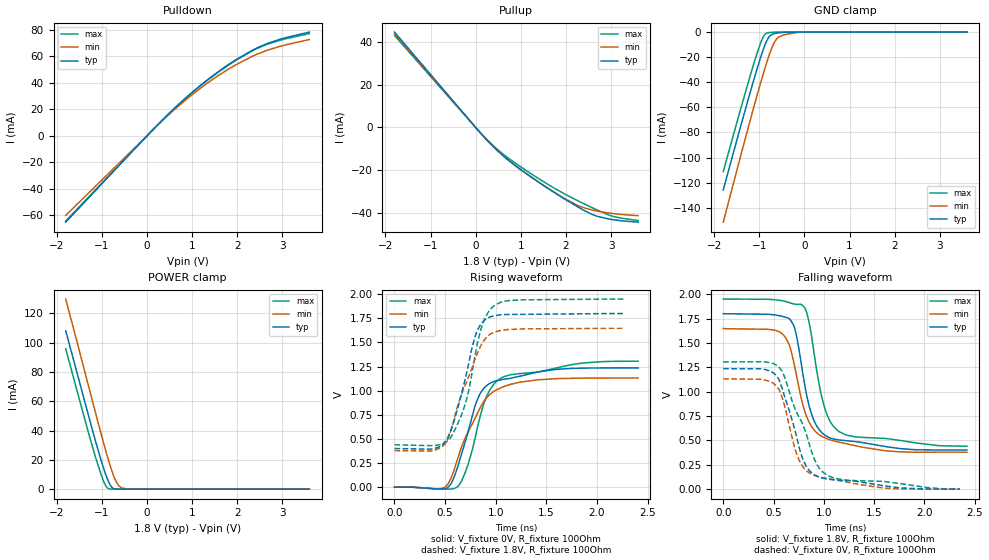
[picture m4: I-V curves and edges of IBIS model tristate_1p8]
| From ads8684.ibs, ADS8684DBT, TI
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|   tristate_1p8 Model
[Model]   tristate_1p8
Model_type   3-state
Polarity   Non-Inverting
Vmeas = 0.9
Vref = 0
Cref = 20pF
Rref = 100
|   typ   min   max
|   (nom PVT)   (fast PVT)   (slow PVT)
C_comp   1.371e-12   1.006e-12   1.720e-12
| Where nom  PVT is Nominal Process, 1.8V, 27C
|   Fast PVT is Strong Process,  1.95V, -40C
|   Slow PVT is Weak Process,   1.65V, 125C
[Voltage Range]   1.8   1.65   1.95
|Junction Temperature
[Temperature Range]   27   125   -40
[Pullup Reference]   1.8   1.65   1.95
[Pulldown Reference]   0   0   0
[Power Clamp Reference]   1.8   1.65   1.95
[GND Clamp Reference]   0   0   0
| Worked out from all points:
|   slope of the pulldown table from 0 to 0.27 V, typ, clamps not added: 28.3 ohm
|   slope of the pullup table from 0 to 0.27 V, typ, clamps not added: 42.5 ohm
|   GND clamp passes 1 mA (typ) near -0.64 V on its own axis
|   POWER clamp passes 1 mA (typ) near -0.76 V on its own axis
|   falling waveform, V_fixture 1.8V, R_fixture 100Ohm: 20-80 % time 175ps typ, 205ps min, 176ps max; typ from 1.8 V to 0.401 V
|   rising waveform, V_fixture 0V, R_fixture 100Ohm: 20-80 % time 222ps typ, 291ps min, 232ps max; typ from 0 V to 1.24 V
|   rising waveform, V_fixture 1.8V, R_fixture 100Ohm: 20-80 % time 199ps typ, 250ps min, 198ps max; typ from 0.401 V to 1.8 V
|   falling waveform, V_fixture 0V, R_fixture 100Ohm: 20-80 % time 220ps typ, 199ps min, 285ps max; typ from 1.24 V to 0 V
[Pulldown]
|   Voltage   I(typ)   I(min)   I(max)
-1.8V     -65.09mA   -59.97mA   -64.2mA
252mV     8.924mA    8.498mA    8.811mA
708mV     23.94mA    22.75mA    23.68mA
1.33V     41.95mA    39.55mA    41.59mA
1.979V    57.51mA    53.74mA    57.14mA
2.453V    66.54mA    61.79mA    66.14mA
2.919V    72.5mA     67.21mA    71.79mA
3.6V      78.26mA    72.63mA    77.11mA
[GND Clamp]
|   Voltage   I(typ)   I(min)   I(max)
-1.8V     -125.8mA   -151.5mA   -111.2mA
-1.188V   -46.12mA   -68.35mA   -32.95mA
-1.039V   -27.91mA   -48.94mA   -15.6mA
-956.8mV  -18.56mA   -38.63mA   -7.307mA
-877.7mV  -10.45mA   -29.02mA   -1.892mA
-786mV    -3.851mA   -18.72mA   -422.1uA
-682.9mV  -1.398mA   -9.3mA     -99.75uA
-612mV    -832uA     -5.278mA   -21.92uA
-567.5mV  -603uA     -3.872mA   -6.378uA
-432.1mV  -155.8uA   -1.97mA    -62.9nA
-150uV    0A         0A         0A
3.6V      0A         0A         0A
[Pullup]
|   Voltage   I(typ)   I(min)   I(max)
-1.8V     44.52mA    43.7mA     42.93mA
144mV     -3.484mA   -3.429mA   -3.353mA
523.2mV   -11.59mA   -11.51mA   -10.98mA
924.2mV   -18.47mA   -18.58mA   -17.31mA
1.764V    -30.63mA   -30.51mA   -28.59mA
2.279V    -37.25mA   -36.57mA   -34.36mA
2.691V    -41.43mA   -39.01mA   -38.5mA
3.065V    -43.1mA    -40.22mA   -41.59mA
3.6V      -44.19mA   -41.16mA   -43.4mA
[POWER Clamp]
|   Voltage   I(typ)   I(min)   I(max)
-1.8V     108.1mA    129.7mA    95.71mA
-1.201V   39.66mA    59.35mA    28.24mA
-1.105V   29.06mA    48.08mA    18.49mA
-969.3mV  15.12mA    32.48mA    6.171mA
-921.6mV  10.73mA    27.2mA     2.821mA
-875.7mV  6.912mA    22.27mA    808.1uA
-786.9mV  1.628mA    13.43mA    15.62uA
-691.2mV  86.61uA    5.777mA    145.8nA
-610.3mV  4.558uA    1.946mA    0A
-565.6mV  916.7nA    930.5uA    0A
-465.2mV  29.51nA    207.3uA    0A
3.6V      0A         0A         0A
[Ramp]
R_load = 100
|   typ   min   max
dV/dt_r   0.741646/2.21853e-10   0.679044/2.91169e-10   0.782971/2.29874e-10
dV/dt_f   0.839441/1.74617e-10   0.760625/2.04263e-10   0.906149/1.75559e-10
[Falling Waveform]
V_fixture = 1.8V
V_fixture_min = 1.65V
V_fixture_max = 1.95V
R_fixture = 100Ohm
|   Time   V(typ)   V(min)   V(max)
0s        1.8V       1.65V      1.95V
604.5ps   1.768V     1.575V     1.929V
704ps     1.671V     1.286V     1.899V
796.5ps   1.15V      845.9mV    1.877V
880ps     763.1mV    639.8mV    1.553V
957.5ps   604.9mV    556mV      1.051V
1.012ns   553mV      526.6mV    823.7mV
1.092ns   516.5mV    498.3mV    648.8mV
1.223ns   497.3mV    466.3mV    554.7mV
2.422ns   401.5mV    379.4mV    440.5mV
[Rising Waveform]
V_fixture = 0V
V_fixture_min = 0V
V_fixture_max = 0V
R_fixture = 100Ohm
|   Time   V(typ)   V(min)   V(max)
0s        1.026nV    295.3nV    1.107nV
488ps     -16.25mV   -5.595mV   -20.24mV
556.5ps   32.29mV    88.5mV     -18.33mV
629.5ps   227.5mV    312.2mV    11.1mV
727ps     574.9mV    572.8mV    237.3mV
816.5ps   901.8mV    757.9mV    607.9mV
943.5ps   1.078V     962.1mV    1.011V
1.144ns   1.129V     1.065V     1.165V
1.581ns   1.219V     1.124V     1.231V
2.407ns   1.236V     1.132V     1.306V
[Rising Waveform]
V_fixture = 1.8V
V_fixture_min = 1.65V
V_fixture_max = 1.95V
R_fixture = 100Ohm
|   Time   V(typ)   V(min)   V(max)
0s        400.9mV    379mV      439.8mV
402.5ps   403.7mV    385.8mV    432.9mV
502ps     472.1mV    450.7mV    463.4mV
546ps     560.1mV    550.7mV    502.3mV
701.5ps   1.134V     1.064V     870.4mV
808ps     1.597V     1.36V      1.431V
885.5ps   1.727V     1.523V     1.733V
991ps     1.778V     1.609V     1.886V
1.256ns   1.791V     1.64V      1.942V
2.271ns   1.8V       1.646V     1.95V
[Falling Waveform]
V_fixture = 0V
V_fixture_min = 0V
V_fixture_max = 0V
R_fixture = 100Ohm
|   Time   V(typ)   V(min)   V(max)
0s        1.236V     1.132V     1.305V
415.5ps   1.227V     1.119V     1.305V
556.5ps   1.117V     1.017V     1.247V
605ps     966.2mV    872mV      1.163V
756ps     420mV      294.2mV    734.2mV
839.5ps   211.9mV    178.8mV    519.9mV
936.5ps   131.2mV    131mV      244mV
1.114ns   94.44mV    95.3mV     109.9mV
1.603ns   33.97mV    10.87mV    78.51mV
2.351ns   5.752nV    481.5nV    2.812nV
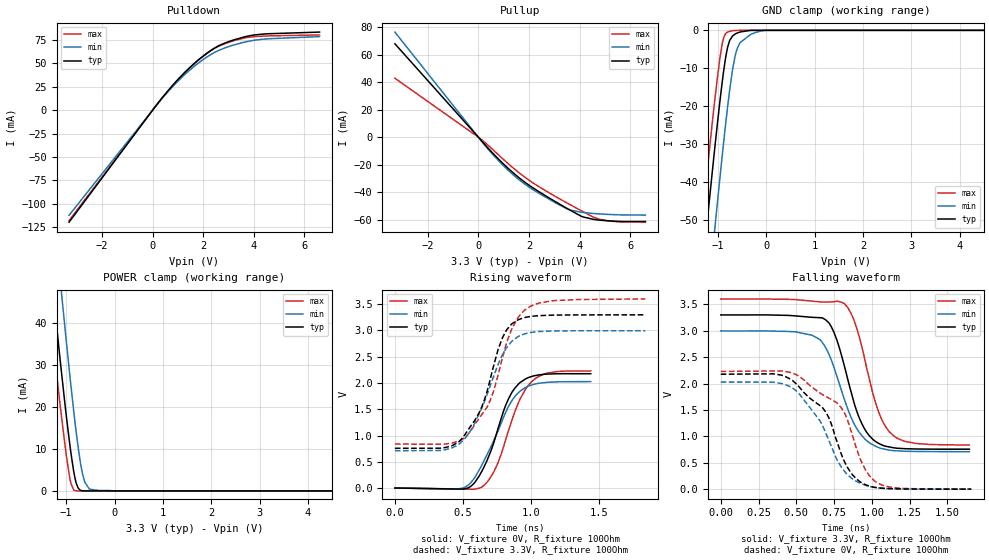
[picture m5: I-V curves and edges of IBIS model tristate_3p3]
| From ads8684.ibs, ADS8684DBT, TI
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|   tristate_3p3 Model
[Model]   tristate_3p3
Model_type   3-state
Polarity   Non-Inverting
Vmeas = 1.65
Vref = 0
Cref = 20pF
Rref = 100
|   typ   min   max
|   (nom PVT)   (fast PVT)   (slow PVT)
C_comp   1.241e-12   9.787e-13   1.501e-12
| Where nom  PVT is Nominal Process, 3.3V, 27C
|   Fast PVT is Strong Process,  3.6V, -40C
|   Slow PVT is Weak Process,   3V, 125C
[Voltage Range]   3.3   3   3.6
|Junction Temperature
[Temperature Range]   27   125   -40
[Pullup Reference]   3.3   3   3.6
[Pulldown Reference]   0   0   0
[Power Clamp Reference]   3.3   3   3.6
[GND Clamp Reference]   0   0   0
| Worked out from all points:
|   slope of the pulldown table from 0 to 0.495 V, typ, clamps not added: 29 ohm
|   slope of the pullup table from 0 to 0.495 V, typ, clamps not added: 48.6 ohm
|   GND clamp passes 1 mA (typ) near -0.64 V on its own axis
|   POWER clamp passes 1 mA (typ) near -0.76 V on its own axis
|   falling waveform, V_fixture 3.3V, R_fixture 100Ohm: 20-80 % time 157ps typ, 178ps min, 155ps max; typ from 3.3 V to 0.758 V
|   rising waveform, V_fixture 0V, R_fixture 100Ohm: 20-80 % time 183ps typ, 217ps min, 187ps max; typ from 0 V to 2.18 V
|   rising waveform, V_fixture 3.3V, R_fixture 100Ohm: 20-80 % time 199ps typ, 218ps min, 227ps max; typ from 0.756 V to 3.3 V
|   falling waveform, V_fixture 0V, R_fixture 100Ohm: 20-80 % time 252ps typ, 232ps min, 266ps max; typ from 2.18 V to 0.001 V
[Pulldown]
|   Voltage   I(typ)   I(min)   I(max)
-3.3V     -119.7mA   -112.3mA   -118mA
447mV     15.52mA    14.81mA    15.34mA
855mV     28.44mA    27.01mA    28.15mA
1.251V    39.8mA     37.59mA    39.45mA
1.647V    49.94mA    46.9mA     49.57mA
2.043V    58.81mA    54.93mA    58.44mA
2.623V    68.98mA    63.99mA    68.49mA
3.065V    73.83mA    68.49mA    73.02mA
3.716V    78.89mA    73.27mA    77.59mA
4.445V    81.5mA     76.06mA    79.28mA
6.6V      83.48mA    78.69mA    80.44mA
[GND Clamp]
|   Voltage   I(typ)   I(min)   I(max)
-3.3V     -328.9mA   -362.5mA   -312.4mA
-1.695V   -112.1mA   -137.4mA   -97.65mA
-1.273V   -57.07mA   -79.97mA   -43.52mA
-1.226V   -51.13mA   -73.73mA   -37.72mA
-1.053V   -29.72mA   -50.99mA   -17.2mA
-912mV    -13.84mA   -33.29mA   -3.71mA
-798.6mV  -4.467mA   -20.17mA   -466.6uA
-696mV    -1.5mA     -10.34mA   -108.1uA
-594mV    -683.5uA   -4.61mA    -10.64uA
-330mV    -17.29uA   -1.156mA   0A
-122.1mV  -35.77nA   -225.6uA   0A
6.6V      0A         0A         0A
[Pullup]
|   Voltage   I(typ)   I(min)   I(max)
-3.3V     68.01mA    76.52mA    42.94mA
0V        0A         0A         0A
390mV     -8.11mA    -8.812mA   -5.98mA
1.109V    -21.55mA   -22.87mA   -18.12mA
1.855V    -33.03mA   -34.46mA   -29.39mA
2.439V    -40.19mA   -41.34mA   -36.53mA
3.477V    -51.57mA   -51.89mA   -47.62mA
3.633V    -53.21mA   -53.05mA   -49.2mA
4.115V    -57.92mA   -54.73mA   -54.02mA
4.559V    -59.84mA   -55.55mA   -58.29mA
5.149V    -60.92mA   -56.21mA   -60.91mA
6.6V      -61.39mA   -56.69mA   -61.87mA
[POWER Clamp]
|   Voltage   I(typ)   I(min)   I(max)
-3.3V     264.7mA    286.7mA    254.7mA
-1.758V   103.3mA    124.9mA    90.94mA
-1.259V   46.13mA    66.14mA    34.43mA
-1.126V   31.26mA    50.44mA    20.48mA
-1.03V    21.08mA    39.31mA    11.34mA
-927.3mV  11.24mA    27.82mA    3.166mA
-831.6mV  3.832mA    17.74mA    133.1uA
-752.4mV  663.2uA    10.37mA    2.888uA
-673.2mV  45.14uA    4.684mA    61.46nA
-614.4mV  5.285uA    2.072mA    0A
-519mV    179.4nA    425uA      0A
6.6V      0A         0A         0A
[Ramp]
R_load = 100
|   typ   min   max
dV/dt_r   1.30697/1.81955e-10   1.21744/2.17227e-10   1.33891/1.86119e-10
dV/dt_f   1.52611/1.57182e-10   1.37183/1.77396e-10   1.6575/1.54768e-10
[Falling Waveform]
V_fixture = 3.3V
V_fixture_min = 3V
V_fixture_max = 3.6V
R_fixture = 100Ohm
|   Time   V(typ)   V(min)   V(max)
0s        3.3V       3V         3.6V
655.5ps   3.248V     2.836V     3.547V
731.5ps   3.076V     2.449V     3.547V
816ps     2.358V     1.721V     3.52V
880ps     1.661V     1.253V     3.212V
949.5ps   1.155V     965.1mV    2.506V
1.03ns    891.4mV    805.3mV    1.583V
1.115ns   801.4mV    740.4mV    1.09V
1.295ns   761.5mV    714.9mV    865.1mV
1.645ns   757.7mV    711.2mV    838mV
[Rising Waveform]
V_fixture = 0V
V_fixture_min = 0V
V_fixture_max = 0V
R_fixture = 100Ohm
|   Time   V(typ)   V(min)   V(max)
0s        1.885nV    556nV      2.045nV
502.5ps   -18.59mV   66.14uV    -21.25mV
577.5ps   77.21mV    163.2mV    -21.91mV
635.5ps   301mV      417.8mV    12.93mV
749.5ps   1.053V     1.034V     429.7mV
835ps     1.696V     1.552V     1.089V
920ps     2.007V     1.844V     1.691V
1.003ns   2.122V     1.959V     2.016V
1.092ns   2.164V     2.004V     2.164V
1.44ns    2.176V     2.027V     2.23V
[Rising Waveform]
V_fixture = 3.3V
V_fixture_min = 3V
V_fixture_max = 3.6V
R_fixture = 100Ohm
|   Time   V(typ)   V(min)   V(max)
0s        756.5mV    710.3mV    837.5mV
377.5ps   775mV      733.5mV    840.4mV
518.5ps   1.03V      955.1mV    972.1mV
622.5ps   1.449V     1.428V     1.339V
699.5ps   2.051V     1.935V     1.664V
794.5ps   2.879V     2.554V     2.512V
900.5ps   3.196V     2.875V     3.227V
995.5ps   3.265V     2.96V      3.459V
1.157ns   3.292V     2.991V     3.564V
1.842ns   3.298V     2.995V     3.598V
[Falling Waveform]
V_fixture = 0V
V_fixture_min = 0V
V_fixture_max = 0V
R_fixture = 100Ohm
|   Time   V(typ)   V(min)   V(max)
0s        2.178V     2.029V     2.23V
354.5ps   2.182V     2.024V     2.24V
473.5ps   2.062V     1.92V      2.2V
688.5ps   1.487V     1.109V     1.768V
794ps     695.8mV    436.9mV    1.555V
864.5ps   299.6mV    211.4mV    1.083V
957ps     86.01mV    75.27mV    370.7mV
1.026ns   31.78mV    30.47mV    137.9mV
1.113ns   12.77mV    10.42mV    43.21mV
1.657ns   1.13mV     1.006mV    1.145mV
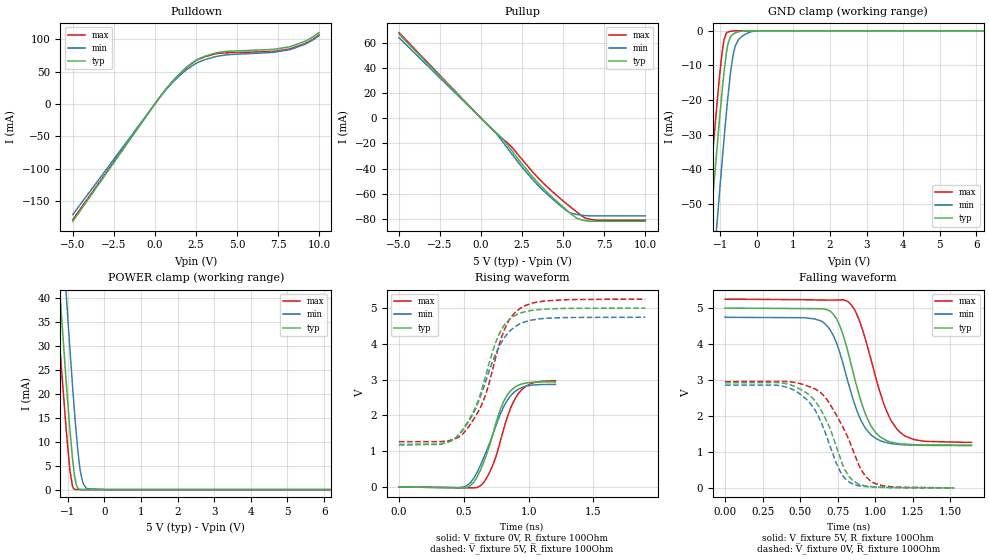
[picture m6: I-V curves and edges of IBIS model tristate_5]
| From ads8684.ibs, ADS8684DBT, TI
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|   tristate_5 Model
[Model]   tristate_5
Model_type   3-state
Polarity   Non-Inverting
Vmeas = 2.5
Vref = 0
Cref = 20pF
Rref = 100
|   typ   min   max
|   (nom PVT)   (fast PVT)   (slow PVT)
C_comp   1.143e-12   9.027e-13   1.378e-12
| Where nom  PVT is Nominal Process, 5V, 27C
|   Fast PVT is Strong Process,  5.25V, -40C
|   Slow PVT is Weak Process,   4.75V, 125C
[Voltage Range]   5   4.75   5.25
|Junction Temperature
[Temperature Range]   27   125   -40
[Pullup Reference]   5   4.75   5.25
[Pulldown Reference]   0   0   0
[Power Clamp Reference]   5   4.75   5.25
[GND Clamp Reference]   0   0   0
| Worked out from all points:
|   slope of the pulldown table from 0 to 0.75 V, typ, clamps not added: 29.8 ohm
|   slope of the pullup table from 0 to 0.75 V, typ, clamps not added: 78.6 ohm
|   GND clamp passes 1 mA (typ) near -0.65 V on its own axis
|   POWER clamp passes 1 mA (typ) near -0.76 V on its own axis
|   falling waveform, V_fixture 5V, R_fixture 100Ohm: 20-80 % time 158ps typ, 162ps min, 173ps max; typ from 5 V to 1.19 V
|   rising waveform, V_fixture 0V, R_fixture 100Ohm: 20-80 % time 160ps typ, 191ps min, 161ps max; typ from 0 V to 2.93 V
|   rising waveform, V_fixture 5V, R_fixture 100Ohm: 20-80 % time 217ps typ, 241ps min, 216ps max; typ from 1.19 V to 5 V
|   falling waveform, V_fixture 0V, R_fixture 100Ohm: 20-80 % time 177ps typ, 175ps min, 203ps max; typ from 2.92 V to 0.002 V
[Pulldown]
|   Voltage   I(typ)   I(min)   I(max)
-5V       -181.3mA   -171mA     -178.8mA
423.3mV   14.73mA    14.07mA    14.55mA
1.3V      41.1mA     38.81mA    40.75mA
2.22V     62.28mA    58.07mA    61.91mA
2.5V      67.15mA    62.38mA    66.73mA
2.97V     72.83mA    67.57mA    72.08mA
3.794V    79.19mA    73.61mA    77.75mA
4.424V    81.21mA    75.82mA    78.99mA
7.159V    84.07mA    79.46mA    80.9mA
8.198V    88.1mA     83.57mA    84.74mA
9.128V    96.49mA    91.86mA    92.96mA
10V       110.2mA    105.3mA    106.3mA
[GND Clamp]
|   Voltage   I(typ)   I(min)   I(max)
-5V       -577.7mA   -618.3mA   -560.4mA
-1.428V   -77.69mA   -101.7mA   -63.48mA
-1.257V   -55.47mA   -78.45mA   -41.71mA
-1.029V   -27.09mA   -48.35mA   -14.59mA
-947mV    -17.69mA   -37.95mA   -6.422mA
-895mV    -12.23mA   -31.56mA   -2.661mA
-780mV    -3.55mA    -18.41mA   -340.8uA
-644.2mV  -952.3uA   -6.904mA   -31.93uA
-582.5mV  -583.3uA   -4.275mA   -6.011uA
-406.8mV  -70.92uA   -1.652mA   -12.28nA
-70.25mV  0A         -86.61uA   0A
10V       0A         0A         0A
[Pullup]
|   Voltage   I(typ)   I(min)   I(max)
-5V       66.84mA    64.02mA    68.09mA
705mV     -8.997mA   -8.747mA   -9.208mA
1.3V      -16.26mA   -18.45mA   -16.2mA
1.78V     -24.14mA   -26.82mA   -21.67mA
3.1V      -46.01mA   -48.11mA   -42mA
4.02V     -58.77mA   -60.3mA    -54.45mA
5.265V    -73.57mA   -74mA      -68.56mA
5.815V    -79.36mA   -76.43mA   -74.35mA
6.309V    -81.31mA   -77.3mA    -79.07mA
6.65V     -81.8mA    -77.59mA   -80.43mA
7.085V    -81.9mA    -77.63mA   -80.98mA
10V       -81.9mA    -77.63mA   -80.98mA
[POWER Clamp]
|   Voltage   I(typ)   I(min)   I(max)
-5V       419.5mA    443.5mA    412.7mA
-1.665V   92.74mA    114.2mA    80.42mA
-1.278V   48.28mA    68.41mA    36.52mA
-1.18V    37.27mA    56.85mA    26mA
-1.038V   21.99mA    40.36mA    12.15mA
-936.5mV  12.07mA    28.85mA    3.76mA
-868.2mV  6.343mA    21.51mA    619.4uA
-815.7mV  2.931mA    16.19mA    63.07uA
-658.3mV  26.25uA    3.895mA    30.15nA
-587.3mV  1.991uA    1.352mA    0A
-454.2mV  22.2nA     198.9uA    0A
10V       0A         0A         0A
[Ramp]
R_load = 100
|   typ   min   max
dV/dt_r   1.75941/1.60029e-10   1.7197/1.90426e-10   1.77984/1.60558e-10
dV/dt_f   2.28617/1.57815e-10   2.14118/1.61973e-10   2.39032/1.72368e-10
[Falling Waveform]
V_fixture = 5V
V_fixture_min = 4.75V
V_fixture_max = 5.25V
R_fixture = 100Ohm
|   Time   V(typ)   V(min)   V(max)
0s        5V         4.75V      5.25V
650.5ps   4.981V     4.619V     5.225V
741ps     4.719V     4.056V     5.225V
822.5ps   3.733V     2.906V     5.171V
882.5ps   2.76V      2.115V     4.789V
966.5ps   1.774V     1.505V     3.671V
1.059ns   1.359V     1.281V     2.336V
1.146ns   1.24V      1.215V     1.637V
1.262ns   1.203V     1.188V     1.343V
1.643ns   1.191V     1.178V     1.268V
[Rising Waveform]
V_fixture = 0V
V_fixture_min = 0V
V_fixture_max = 0V
R_fixture = 100Ohm
|   Time   V(typ)   V(min)   V(max)
0s        2.877nV    1.171uV    2.983nV
503ps     -22.3mV    2.11mV     -22.2mV
577ps     133.9mV    247.3mV    -24.42mV
627ps     461.8mV    593.6mV    32.52mV
727ps     1.514V     1.499V     643.8mV
783ps     2.18V      2.046V     1.295V
857ps     2.671V     2.529V     2.165V
918ps     2.839V     2.727V     2.594V
984ps     2.909V     2.82V      2.827V
1.206ns   2.932V     2.866V     2.968V
[Rising Waveform]
V_fixture = 5V
V_fixture_min = 4.75V
V_fixture_max = 5.25V
R_fixture = 100Ohm
|   Time   V(typ)   V(min)   V(max)
0s        1.19V      1.176V     1.266V
356ps     1.227V     1.225V     1.278V
491.5ps   1.602V     1.586V     1.479V
591ps     2.235V     2.187V     1.979V
655.5ps   2.939V     2.805V     2.451V
775.5ps   4.291V     3.948V     3.999V
848ps     4.673V     4.33V      4.653V
899ps     4.802V     4.488V     4.888V
1.127ns   4.971V     4.712V     5.199V
1.899ns   5V         4.745V     5.25V
[Falling Waveform]
V_fixture = 0V
V_fixture_min = 0V
V_fixture_max = 0V
R_fixture = 100Ohm
|   Time   V(typ)   V(min)   V(max)
0s        2.924V     2.861V     2.953V
375.5ps   2.921V     2.838V     2.963V
562.5ps   2.58V      2.375V     2.815V
622ps     2.285V     1.994V     2.697V
694.5ps   1.704V     1.232V     2.363V
767.5ps   841.3mV    455.3mV    1.833V
847ps     222.7mV    118.8mV    1.113V
913.5ps   79.46mV    48.96mV    465.8mV
1ns       28.78mV    22.85mV    123.7mV
1.527ns   1.853mV    1.713mV    2.368mV
